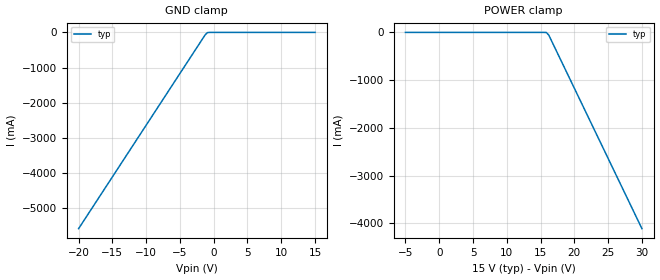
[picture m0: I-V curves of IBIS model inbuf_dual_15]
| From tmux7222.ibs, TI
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| inbuf_dual_15
[Model]   inbuf_dual_15
Model_type   Input
Vinl = 0.8
Vinh = 1.3
|   typ   min   max
C_comp   4.014581e-13   NA   NA
[Voltage Range]   15   NA   NA
[Temperature Range]   27   NA   NA
[Power Clamp Reference]   15   NA   NA
[GND Clamp Reference]   0   NA   NA
[GND Clamp]
|   Voltage   I(typ)   I(min)   I(max)
-20V      -5.586A    NA         NA
-1.263V   -68.48mA   NA         NA
-909.1mV  -5.152mA   NA         NA
-555.6mV  -13.09uA   NA         NA
15V       929.5nA    NA         NA
[POWER Clamp]
|   Voltage   I(typ)   I(min)   I(max)
-5V       1.152uA    NA         NA
15.51V    -7.81uA    NA         NA
15.86V    -2.424mA   NA         NA
16.21V    -55.95mA   NA         NA
30V       -4.108A    NA         NA
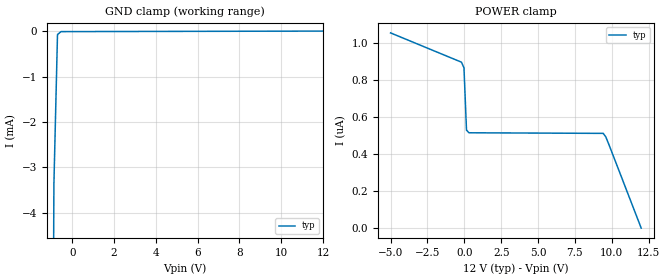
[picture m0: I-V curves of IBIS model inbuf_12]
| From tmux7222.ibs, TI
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| inbuf_12
[Model]   inbuf_12
Model_type   Input
Vinl = 0.8
Vinh = 1.3
|   typ   min   max
C_comp   4.014581e-13   NA   NA
[Voltage Range]   12   NA   NA
[Temperature Range]   27   NA   NA
[Power Clamp Reference]   12   NA   NA
[GND Clamp Reference]   0   NA   NA
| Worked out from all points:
|   GND clamp passes 1 mA (typ) near -0.76 V on its own axis
[GND Clamp]
|   Voltage   I(typ)   I(min)   I(max)
-5V       -1.141A    NA         NA
-1.051V   -20.98mA   NA         NA
-878.8mV  -3.369mA   NA         NA
-707.1mV  -74.76uA   NA         NA
-535.4mV  -10.83uA   NA         NA
12V       842.9nA    NA         NA
[POWER Clamp]
|   Voltage   I(typ)   I(min)   I(max)
-5V       1.054uA    NA         NA
-191.9mV  896nA      NA         NA
-20.2mV   865.4nA    NA         NA
151.5mV   528.7nA    NA         NA
323.2mV   514.8nA    NA         NA
9.424V    511.6nA    NA         NA
9.596V    492.8nA    NA         NA
9.768V    459.7nA    NA         NA
12V       -74.05pA   NA         NA
